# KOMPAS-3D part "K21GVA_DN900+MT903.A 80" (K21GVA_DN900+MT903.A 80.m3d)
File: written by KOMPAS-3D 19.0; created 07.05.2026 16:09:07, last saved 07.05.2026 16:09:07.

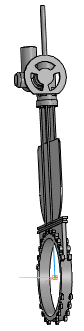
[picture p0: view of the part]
Document properties: Автор: Энергия; Полное имя файла: ..\K21GVA_DN50-DN1000+MT903.A\K21GVA_DN900+MT903.A 80.a3d

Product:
- Part/product: K21GVA_DN900+MT903.A 80
    Масса: 772.301

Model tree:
1. Операция без истории:1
